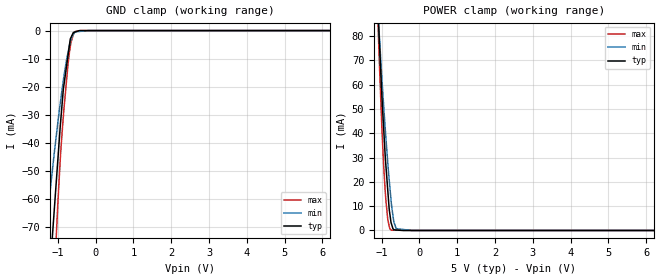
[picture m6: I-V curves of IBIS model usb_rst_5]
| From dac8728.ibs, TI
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|   usb_rst_5 Model
[Model]   usb_rst_5
Model_type   Input
Vinl = 0.8
Vinh = 3.3
|   typ   min   max
|   (nom PVT)   (Fast PVT)   (slow PVT)
|C_comp from frequency method(F=50MHz)
|Average
|C_comp   8.308e-12   6.943e-12   9.649e-12
|C_comp from L-C Tank method(L=1nH)
|Resonant Frequency(Hz)   1.81e9   1.96e9   1.69e9
C_comp   7.74e-12   6.6e-12   8.878e-12
| Where nom  PVT is Nominal Process,  5V,  33C
|   Fast PVT is Strong Process,   5.5V,  -40C
|   Slow PVT is Weak Process,   4.5V,  113C
[Voltage Range]   5   4.5   5.5
|Ambient Temperature   25   105   -40
|Junction Temperature
[Temperature Range]   33   113   -40
[Power Clamp Reference]   5   4.5   5.5
[GND Clamp Reference]   0   0   0
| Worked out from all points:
|   GND clamp passes 1 mA (typ) near -0.60 V on its own axis
|   POWER clamp passes 1 mA (typ) near -0.70 V on its own axis
[GND Clamp]
|   Voltage   I(typ)   I(min)   I(max)
-5V       -981.7mA   -687.3mA   -1.357A
-1.368V   -120.3mA   -78.69mA   -173.2mA
-1.228V   -91.1mA    -60.29mA   -129.3mA
-1.14V    -72.57mA   -49.33mA   -102.3mA
-1.089V   -62.95mA   -43.03mA   -86.87mA
-1.001V   -46.36mA   -32.99mA   -61.99mA
-929.5mV  -33.02mA   -25.32mA   -44.54mA
-855mV    -20.97mA   -17.76mA   -30.72mA
-693mV    -5.221mA   -5.274mA   -7.735mA
-670mV    -2.985mA   -4.048mA   -5.704mA
-544.5mV  -503.3uA   -473.7uA   -353.4uA
10V       0A         0A         0A
[POWER Clamp]
|   Voltage   I(typ)   I(min)   I(max)
-5V       1.399A     1.179A     1.687A
-1.111V   95.69mA    93.54mA    92.87mA
-1.056V   76.86mA    79.04mA    67.78mA
-984.5mV  52.94mA    60.5mA     39.43mA
-907.5mV  31.53mA    42.75mA    16.99mA
-836mV    16.41mA    27.83mA    4.45mA
-795mV    8.276mA    20.19mA    1.601mA
-742.5mV  2.885mA    11.14mA    115.5uA
-679.5mV  421.1uA    3.912mA    105.7uA
-612mV    201.1uA    759.8uA    95.21uA
-202.5mV  26.43nA    5.18nA     31.5uA
10V       0A         0A         0A
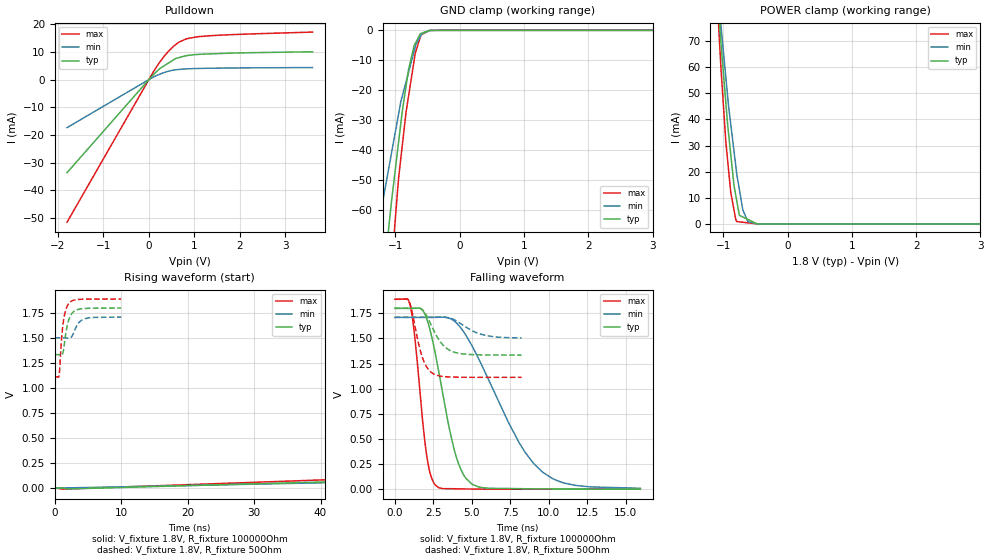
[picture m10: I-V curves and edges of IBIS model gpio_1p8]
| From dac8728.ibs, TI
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|   gpio_1p8 Model
[Model]   gpio_1p8
Model_type   I/O_open_drain
Polarity   Non-Inverting
Enable   Active-Low
Vinl = 0.3
Vinh = 1.5
Vmeas = 0.9
Vref = 1.8
Cref = 10pF
Rref = 100000
|   typ   min   max
|   (nom PVT)   (Fast PVT)   (slow PVT)
|C_comp from frequency method(F=50MHz)
|Average
C_comp   1.004e-11   8.385e-12   1.147e-11
|ON state : BUFFER OUTPUT TURNED LOW
|C_comp   1.029e-11   8.618e-12   1.168e-11
|OFF state: BUFFER IN HIGH IMPEDANCE
|C_comp   9.783e-12   8.152e-12   1.126e-11
|C_comp from L-C Tank method(L=1nH)
|Average
|C_comp   9.038e-12   7.741e-12   1.029e-11
|ON state : BUFFER OUTPUT TURNED LOW
|Resonant Frequency(Hz)   1.670e+09   1.800e+09   1.570e+09
|C_comp   9.092e-12   7.826e-12   1.029e-11
|OFF state: BUFFER IN HIGH IMPEDANCE
|Resonant Frequency(Hz)   1.680e+09   1.820e+09   1.570e+09
|C_comp   8.984e-12   7.655e-12   1.029e-11
| Where nom  PVT is Nominal Process,  1.8V,  33C
|   Fast PVT is Strong Process,   1.89V,  -40C
|   Slow PVT is Weak Process,   1.71V,  113C
[Voltage Range]   1.8   1.71   1.89
|Ambient Temperature   25   105   -40
|Junction Temperature
[Temperature Range]   33   113   -40
[Pullup Reference]   1.8   1.71   1.89
[Pulldown Reference]   0   0   0
[Power Clamp Reference]   1.8   1.71   1.89
[GND Clamp Reference]   0   0   0
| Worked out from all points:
|   slope of the pulldown table from 0 to 0.27 V, typ, clamps not added: 63 ohm
|   GND clamp passes 1 mA (typ) near -0.60 V on its own axis
|   POWER clamp passes 1 mA (typ) near -0.56 V on its own axis
|   falling waveform, V_fixture 1.8V, R_fixture 100000Ohm: 20-80 % time 1.41ns typ, 3.35ns min, 736ps max; typ from 1.8 V to 0.001 V
|   rising waveform, V_fixture 1.8V, R_fixture 100000Ohm: 20-80 % time 1.41us typ, 1.66us min, 1.16us max; typ from 0.001 V to 1.8 V
|   falling waveform, V_fixture 1.8V, R_fixture 50Ohm: 20-80 % time 1.04ns typ, 1.45ns min, 737ps max; typ from 1.8 V to 1.33 V
|   rising waveform, V_fixture 1.8V, R_fixture 50Ohm: 20-80 % time 832ps typ, 1.06ns min, 664ps max; typ from 1.33 V to 1.8 V
[Pulldown]
|   Voltage   I(typ)   I(min)   I(max)
-1.8V     -33.62mA   -17.36mA   -51.51mA
94.5mV    1.679mA    857.6uA    2.685mA
252mV     4.1mA      2.016mA    6.598mA
332.6mV   4.946mA    2.529mA    8.364mA
451.7mV   6.194mA    3.101mA    10.6mA
574.6mV   7.482mA    3.512mA    12.48mA
667.2mV   7.964mA    3.67mA     13.57mA
835.4mV   8.669mA    3.878mA    14.78mA
1.089V    9.099mA    4.018mA    15.5mA
1.784V    9.552mA    4.186mA    16.21mA
3.6V      10.05mA    4.348mA    17.16mA
[GND Clamp]
|   Voltage   I(typ)   I(min)   I(max)
-1.8V     -217.1mA   -140.2mA   -312.5mA
-1.262V   -97.62mA   -64.76mA   -140mA
-1.217V   -88.59mA   -59.47mA   -125.7mA
-1.058V   -56.53mA   -40.62mA   -77.97mA
-952.6mV  -37.5mA    -28.06mA   -49.75mA
-916.6mV  -31.03mA   -23.81mA   -42.75mA
-835.4mV  -18.63mA   -17.2mA    -27.34mA
-797.4mV  -13.17mA   -14.11mA   -22.1mA
-693.6mV  -4.462mA   -5.652mA   -7.799mA
-612mV    -1.105mA   -2.018mA   -2.18mA
-447.9mV  -29.85uA   -62.66uA   -17.6uA
3.6V      0A         0A         0A
[POWER Clamp]
|   Voltage   I(typ)   I(min)   I(max)
-1.8V     358mA      304.5mA    426.4mA
-1.132V   102.5mA    100.6mA    102.4mA
-1.033V   68.07mA    74.92mA    58.33mA
-960.1mV  46.27mA    55.98mA    31.26mA
-884.5mV  26.67mA    38.19mA    12.16mA
-833.4mV  14.7mA     27.77mA    5.309mA
-790mV    8.732mA    18.93mA    916.8uA
-750.6mV  3.31mA     13.22mA    803.6uA
-696mV    2.662mA    5.386mA    646.8uA
-619mV    1.749mA    918.7uA    426uA
-470.3mV  197.2nA    12.34uA    3.023nA
3.6V      0A         0A         0A
[Ramp]
R_load = 100000
|   typ   min   max
dV/dt_r   1.07848/1.40675e-06   1.02257/1.65773e-06   1.13334/1.1625e-06
dV/dt_f   1.07941/1.41976e-09   1.02492/3.40729e-09   1.13361/7.37453e-10
[Falling Waveform]
V_fixture = 1.8V
V_fixture_min = 1.71V
V_fixture_max = 1.89V
R_fixture = 100000Ohm
|   Time   V(typ)   V(min)   V(max)
0s        1.8V       1.71V      1.89V
1ns       1.8V       1.71V      1.826V
1.3ns     1.801V     1.71V      1.504V
2.09ns    1.687V     1.71V      312.8mV
2.8ns     1.212V     1.711V     19.57mV
4ns       316.8mV    1.654V     4.269mV
5.05ns    47.41mV    1.416V     1.888mV
8.07ns    5.651mV    464mV      648.1uV
9.59ns    3.157mV    171.2mV    629.2uV
15.95ns   1.04mV     9.397mV    636.9uV
[Rising Waveform]
V_fixture = 1.8V
V_fixture_min = 1.71V
V_fixture_max = 1.89V
R_fixture = 100000Ohm
|   Time   V(typ)   V(min)   V(max)
0s        963.7uV    1.774mV    636.8uV
180.2ns   299.7mV    238.5mV    384.5mV
342ns     532.3mV    431.8mV    665.8mV
527.1ns   752.6mV    621.4mV    918.4mV
723.7ns   942mV      791mV      1.123V
1.208us   1.265V     1.097V     1.452V
1.832us   1.501V     1.34V      1.669V
2.612us   1.651V     1.508V     1.792V
3.906us   1.751V     1.633V     1.864V
8us       1.798V     1.706V     1.89V
[Falling Waveform]
V_fixture = 1.8V
V_fixture_min = 1.71V
V_fixture_max = 1.89V
R_fixture = 50Ohm
|   Time   V(typ)   V(min)   V(max)
0s        1.8V       1.71V      1.89V
905ps     1.8V       1.71V      1.876V
1.045ns   1.8V       1.71V      1.812V
1.76ns    1.79V      1.71V      1.324V
2.105ns   1.715V     1.71V      1.207V
2.455ns   1.602V     1.71V      1.153V
3.1ns     1.439V     1.711V     1.123V
3.86ns    1.363V     1.686V     1.115V
5.515ns   1.337V     1.546V     1.113V
8.235ns   1.335V     1.505V     1.113V
[Rising Waveform]
V_fixture = 1.8V
V_fixture_min = 1.71V
V_fixture_max = 1.89V
R_fixture = 50Ohm
|   Time   V(typ)   V(min)   V(max)
0s        1.334V     1.503V     1.113V
635ps     1.334V     1.503V     1.122V
745ps     1.332V     1.503V     1.194V
1.035ns   1.328V     1.503V     1.5V
1.285ns   1.369V     1.503V     1.66V
1.655ns   1.546V     1.501V     1.782V
2.135ns   1.688V     1.498V     1.848V
2.945ns   1.77V      1.57V      1.88V
4.48ns    1.796V     1.693V     1.889V
9.995ns   1.8V       1.71V      1.89V
